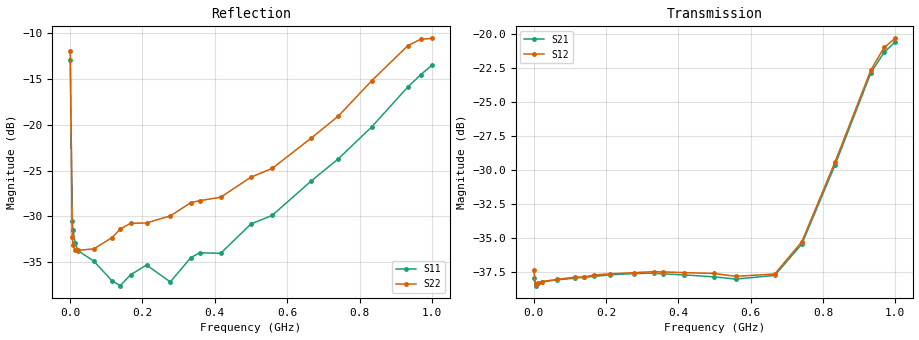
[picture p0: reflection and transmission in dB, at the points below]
!Keysight Technologies,N5232A,MY52221221,A.10.65.11
!Date: Thursday, June 15, 2023 18:09:51
!Correction: S11(Full 2 Port(1,4))
!S41(Full 2 Port(1,4))
!S14(Full 2 Port(1,4))
!S44(Full 2 Port(1,4))
!S2P File: Measurements: S11, S41, S14, S44:
# Hz S  RI  R 50
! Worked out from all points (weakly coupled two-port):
!   16001 points, 300 kHz to 1 GHz, reference 50 ohm
!   highest |S21| = -20.57 dB at 1 GHz (marker M1); lowest = -38.5 dB at 7.86 MHz (marker M2)
!   lowest |S11| = -37.6 dB at 138.5 MHz (marker M3), VSWR 1.03, Z = 49.1 + j0.948 ohm
!   |S11| at or under -10 dB: start of sweep to end of sweep
!   |S22| runs from -33.8 to -10.5 dB; largest |S21 - S12| = 0.16
!   S11 on the Smith chart (normalised r, x): 300 kHz: 0.77, +0.34; 65.47 MHz: 0.97, +0.02; 1 GHz: 1.10, -0.44
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300000  -0.0865 0.2094  -0.0126 -0.00142  -0.013 0.00393  -0.0668 0.2442
5735869  -0.0232 0.0188  -0.012 -7.57e-06  -0.0121 -0.000288  0.0111 0.0216
7860231  -0.0216 0.0155  -0.0119 -6.86e-05  -0.0121 -0.00035  0.0129 0.0179
1.354602e7  -0.0195 0.0116  -0.0122 0.000172  -0.0122 -0.000555  0.0155 0.0136
2.235588e7  -0.018 0.00976  -0.0123 0.000335  -0.0123 -0.000819  0.0173 0.0112
6.546794e7  -0.0162 0.00786  -0.0124 0.00158  -0.0124 -0.0019  0.0191 0.00876
1.154529e8  -0.0117 0.00783  -0.0123 0.0031  -0.0124 -0.00318  0.0228 0.00807
1.385085e8  -0.00904 0.00965  -0.0122 0.00379  -0.0123 -0.00351  0.0252 0.00966
1.669375e8  -0.0078 0.013  -0.012 0.00465  -0.0123 -0.0043  0.026 0.0127
2.112367e8  -0.0081 0.0151  -0.0116 0.00596  -0.012 -0.00538  0.0247 0.0154
2.76967e8  -0.00213 0.0137  -0.0107 0.0077  -0.0114 -0.00682  0.0276 0.0158
3.33575e8  0.00349 0.0185  -0.00968 0.00902  -0.0106 -0.0082  0.0302 0.0223
3.581301e8  0.00394 0.0196  -0.00923 0.00937  -0.0101 -0.00875  0.0294 0.0249
4.161752e8  0.00842 0.018  -0.00812 0.0102  -0.00876 -0.01  0.0294 0.0274
5.0015e8  0.0192 0.0214  -0.00675 0.0109  -0.0061 -0.0117  0.0336 0.0394
5.583825e8  0.0255 0.0193  -0.00629 0.0109  -0.00349 -0.0124  0.0335 0.047
6.667875e8  0.0463 0.0171  -0.00777 0.0104  0.00403 -0.0125  0.0429 0.0729
7.417025e8  0.0649 0.00658  -0.0127 0.0112  0.0127 -0.0117  0.0545 0.0974
8.33425e8  0.0958 -0.0164  -0.0249 0.0217  0.0317 -0.0119  0.0955 0.145
9.328951e8  0.1275 -0.097  -0.0204 0.0693  0.0647 -0.0357  0.2148 0.1626
9.691967e8  0.1173 -0.1464  0.00585 0.0854  0.0683 -0.0575  0.2625 0.1301
1e9  0.0893 -0.1909  0.035 0.0868  0.0596 -0.0758  0.2834 0.086
